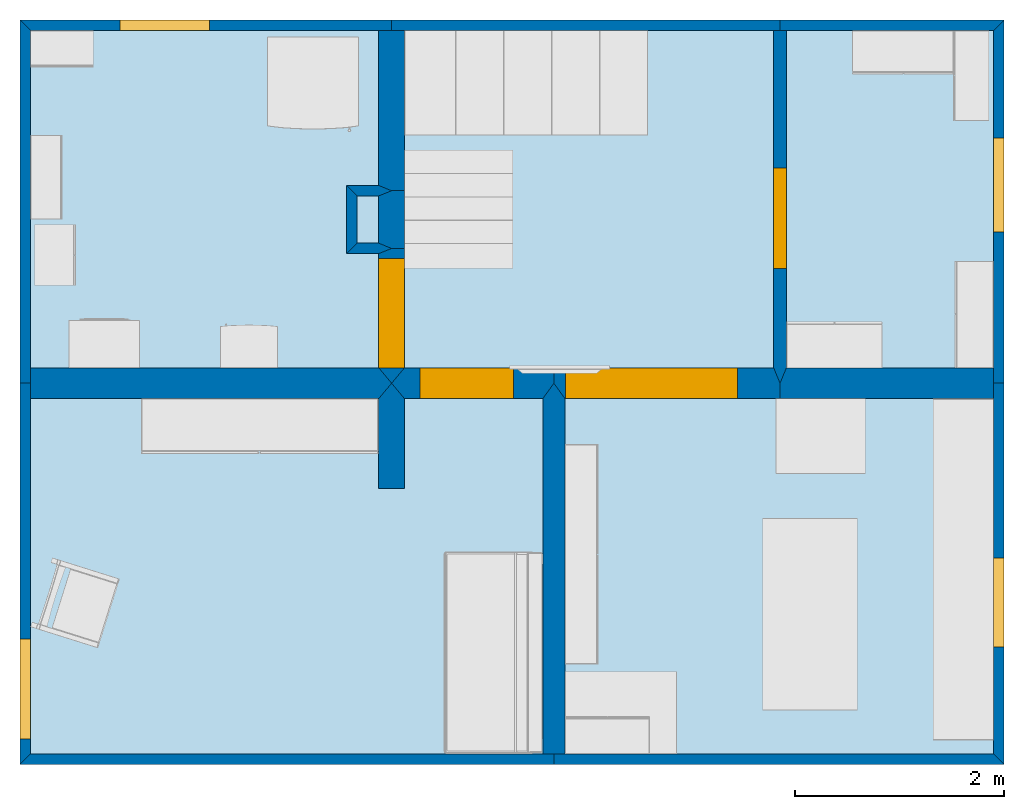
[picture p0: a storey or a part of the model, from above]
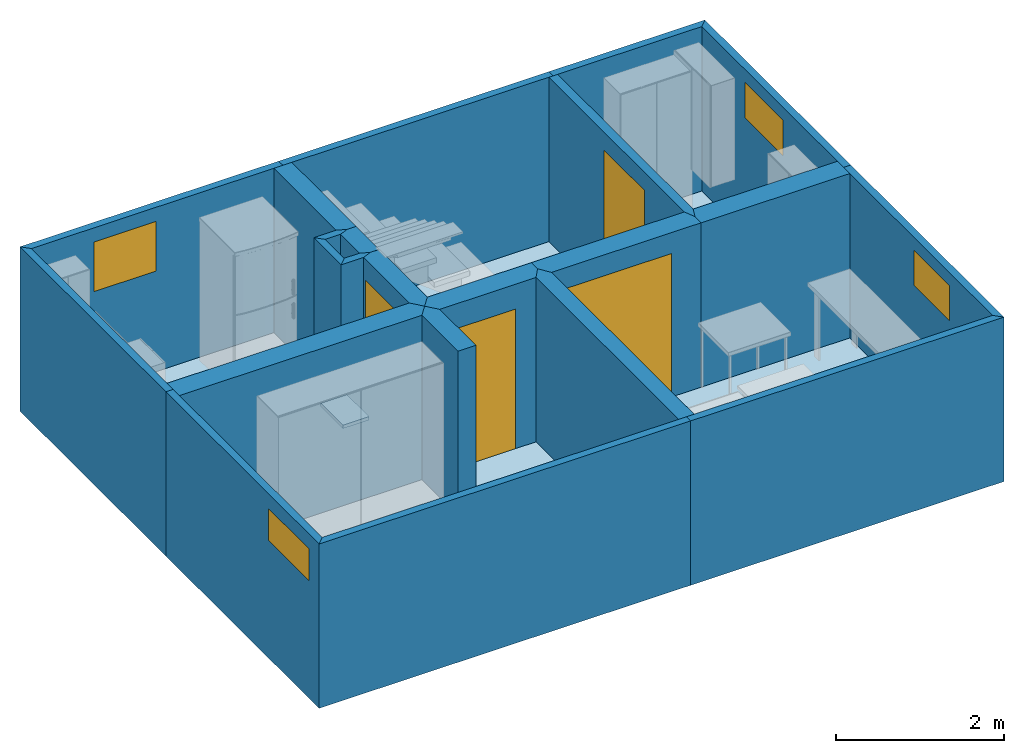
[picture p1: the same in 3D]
Properties of the parts of a building model (IFC4)

# File
Description: ViewDefinition [CoordinationView]
Time: 2025-05-14T06:58:39
Author: Metaroom
Written by: IfcOpenShell v0.7.0-f7c03db75
Made in: INDUSTRY_FOUNDATION_CLASSES_4

# IfcSite, Site
MetaroomProperties - NorthHeading: (np.float64(-0.077), np.float64(0.997), np.float64(0.0)); UpVector: (np.float64(0.0), np.float64(0.0), np.float64(1.0)); IsLeftHandedCoordinateSystem: no

# IfcBuilding, Building
Pset_BuildingCommon - NumberOfStoreys: 3

# IfcBuildingStorey (3)
In: Building
Pset_BuildingStoreyCommon - EntranceLevel: no; GrossPlannedArea: 0 m2; NetPlannedArea: 0 m2
Qto_BuildingStoreyBaseQuantities - GrossHeight: 0 m; NetHeight: 0 m; GrossPerimeter: 0 m; GrossFloorArea: 0 m2; NetFloorArea: 0 m2; GrossVolume: 0; NetVolume: 0
Name | Elevation (m)
Story 0 | 0.05
Story 1 | 2.86083
Story 2 | 5.71135

# IfcSpace (20)
Type - PredefinedType: SPACE
Name | In
001 | Story 0
002 | Story 0
003 | Story 0
004 | Story 0
005 | Story 0
006 | Story 0
007 | Story 1
008 | Story 1
009 | Story 1
010 | Story 1
011 | Story 1
012 | Story 2
013 | Story 2
014 | Story 2
015 | Story 2
016 | Story 2
017 | Story 2
018 | Story 2
019 | Story 2
020 | Story 2

# IfcBuildingElementProxy: PointOfInterest (6)
MetaroomProperties - Tag 0: Green
Name | In
PointOfInterest | 012
PointOfInterest | 014
PointOfInterest | 015
PointOfInterest | 016
PointOfInterest | 019
PointOfInterest | 019 | MetaroomProperties - Name: Test

# IfcDoor: Metaroom Door area (17)
Type - PredefinedType: DOOR
Name | In | OverallHeight (m) | OverallWidth (m)
Metaroom Door area | Story 2 | 2.28109 | 0.85378
Metaroom Door area | Story 2 | 2.25869 | 0.809477
Metaroom Door area | Story 2 | 2.47688 | 0.824479
Metaroom Door area | Story 2 | 2.28495 | 0.862626
Metaroom Door area | Story 2 | 2.47688 | 0.857412
Metaroom Door area | Story 1 | 2.05556 | 0.740228
Metaroom Door area | Story 1 | 2.10004 | 0.906087
Metaroom Door area | Story 1 | 2.1948 | 0.947792
Metaroom Door area | Story 1 | 2.2057 | 0.79263
Metaroom Door area | Story 1 | 2.12237 | 0.876066
Metaroom Door area | Story 1 | 2.24737 | 2.58648
Metaroom Door area | Story 1 | 2.08665 | 0.840058
Metaroom Door area | Story 1 | 2.11225 | 0.921124
Metaroom Door area | Story 0 | 2.12788 | 0.961672
Metaroom Door area | Story 0 | 2.08591 | 1.64665
Metaroom Door area | Story 0 | 2.08575 | 1.16787
Metaroom Door area | Story 0 | 2.02951 | 0.895735

# IfcEnergyConversionDevice, s5
In: 016
Type - Material: Wood light 0.01 m
MetaroomProperties - Name: s5

# IfcFlowTerminal (3)
Type - Material: Wood light 0.01 m
Name | In | Name
sb1 | 015 | sb1
s1 | 016 | s1
s7 | 016 | s7

# IfcFurniture (11)
PredefinedType: USERDEFINED
Name | In | Name
test1 | 015 | test1
test2 | 015 | test2
tes t 3 | 015 | tes t 3
s2 | 016 | s2
sb2 | 016 | sb2
s4 | 016 | s4
s6 | 016 | s6
s3 | 016 | s3
box | 016 | box
test 5 | 019 | test 5
test 6 | 019 | test 6

# IfcFurniture: Bathtub
In: 013
Type - ElementType: Bathtub; PredefinedType: USERDEFINED

# IfcFurniture: Bed (4)
Type - ElementType: Bed; PredefinedType: USERDEFINED
Name | In
Bed | 012
Bed | 014
2 x Bed | 016

# IfcFurniture: Chair (17)
Type - ElementType: Chair; PredefinedType: USERDEFINED
Name | In
Chair | 012
Chair | 014
2 x Chair | 015
Chair | 016
Chair | 008
10 x Chair | 009
Chair | 003

# IfcFurniture: Oven
In: 009
Type - ElementType: Oven; PredefinedType: USERDEFINED

# IfcFurniture: Refrigerator (3)
Type - ElementType: Refrigerator; PredefinedType: USERDEFINED
Name | In
Refrigerator | 009
2 x Refrigerator | 005

# IfcFurniture: STAIRS (5)
Type - ElementType: STAIRS; PredefinedType: USERDEFINED
Name | In
STAIRS | 019
2 x STAIRS | 011
2 x STAIRS | 002

# IfcFurniture: Sink (3)
Type - ElementType: Sink; PredefinedType: USERDEFINED
Name | In
Sink | 013
Sink | 009
Sink | 010

# IfcFurniture: Sofa (3)
Type - ElementType: Sofa; PredefinedType: USERDEFINED
Name | In
2 x Sofa | 009
Sofa | 003

# IfcFurniture: Storage (35)
Type - ElementType: Storage; PredefinedType: USERDEFINED
Name | In
2 x Storage | 012
2 x Storage | 013
2 x Storage | 014
Storage | 015
2 x Storage | 016
11 x Storage | 009
Storage | 010
3 x Storage | 011
5 x Storage | 001
Storage | 003
2 x Storage | 004
3 x Storage | 005

# IfcFurniture: Table (11)
Type - ElementType: Table; PredefinedType: USERDEFINED
Name | In
Table | 012
Table | 014
Table | 015
Table | 016
Table | 008
Table | 009
Table | 010
4 x Table | 004

# IfcFurniture: Television (2)
Type - ElementType: Television; PredefinedType: USERDEFINED
Name | In
Television | 009
Television | 002

# IfcFurniture: Toilet (2)
Type - ElementType: Toilet; PredefinedType: USERDEFINED
Name | In
Toilet | 013
Toilet | 010

# IfcFurniture: Washerdryer
In: 005
Type - ElementType: Washerdryer; PredefinedType: USERDEFINED

# IfcOpeningElement: OPENING (33)
Qto_OpeningElementBaseQuantities - Volume: 0
Name | In | Width (m) | Height (m) | Perimeter (m) | Area (m2)
Metaroom Opening | Story 2 | 0.889001 | 1.20373 | 4.18546 | 1.07012
Metaroom Opening | Story 2 | 0.85378 | 2.28109 | 6.26974 | 1.94755
Metaroom Opening | Story 2 | 0.89696 | 1.30003 | 4.39398 | 1.16608
Metaroom Opening | Story 2 | 0.835934 | 1.17514 | 4.02214 | 0.982337
Metaroom Opening | Story 2 | 2.25869 | 0.809477 | 6.13633 | 1.82836
Metaroom Opening | Story 2 | 0.82448 | 2.47688 | 6.60272 | 2.04214
Metaroom Opening | Story 2 | 1.74621 | 1.28411 | 6.06064 | 2.24233
Metaroom Opening | Story 2 | 2.28495 | 0.862626 | 6.29516 | 1.97106
Metaroom Opening | Story 2 | 1.81029 | 1.26005 | 6.14068 | 2.28106
Metaroom Opening | Story 2 | 0.926479 | 1.20518 | 4.26333 | 1.11658
Metaroom Opening | Story 2 | 0.912154 | 1.19392 | 4.21215 | 1.08904
Metaroom Opening | Story 2 | 0.857411 | 2.47688 | 6.66859 | 2.12371
Metaroom Opening | Story 2 | 0.847895 | 1.14438 | 3.98455 | 0.970312
Metaroom Opening | Story 1 | 0.458122 | 1.03326 | 2.98277 | 0.47336
Metaroom Opening | Story 1 | 2.05556 | 0.740228 | 5.59157 | 1.52158
Metaroom Opening | Story 1 | 2.10004 | 0.906087 | 6.01226 | 1.90282
Metaroom Opening | Story 1 | 0.844887 | 1.10469 | 3.89916 | 0.933341
Metaroom Opening | Story 1 | 2.1948 | 0.947791 | 6.28518 | 2.08021
Metaroom Opening | Story 1 | 0.951705 | 1.22256 | 4.34853 | 1.16352
Metaroom Opening | Story 1 | 2.2057 | 0.79263 | 5.99666 | 1.7483
Metaroom Opening | Story 1 | 2.12237 | 0.876066 | 5.99687 | 1.85934
Metaroom Opening | Story 1 | 2.24737 | 2.58648 | 9.66769 | 5.81276
Metaroom Opening | Story 1 | 0.529042 | 0.975744 | 3.00957 | 0.51621
Metaroom Opening | Story 1 | 2.08666 | 0.840058 | 5.85343 | 1.75291
Metaroom Opening | Story 1 | 2.11226 | 0.921124 | 6.06676 | 1.94565
Metaroom Opening | Story 0 | 0.899296 | 0.516043 | 2.83068 | 0.464075
Metaroom Opening | Story 0 | 2.12788 | 0.961672 | 6.1791 | 2.04632
Metaroom Opening | Story 0 | 1.64665 | 2.08591 | 7.46511 | 3.43475
Metaroom Opening | Story 0 | 1.16787 | 2.08575 | 6.50724 | 2.43589
Metaroom Opening | Story 0 | 0.895735 | 2.02951 | 5.8505 | 1.81791
Metaroom Opening | Story 0 | 0.960611 | 0.461575 | 2.84437 | 0.443394
Metaroom Opening | Story 0 | 0.850732 | 0.509087 | 2.71964 | 0.433096
Metaroom Opening | Story 0 | 0.857327 | 0.721237 | 3.15713 | 0.618336

# IfcSlab: Metaroom Ceiling (9)
In: Story 2
Type - PredefinedType: ROOF

# IfcSlab: Metaroom Slab (20)
Type - PredefinedType: FLOOR
Name | In
9 x Floor | Story 2
5 x Floor | Story 1
6 x Floor | Story 0

# IfcWallStandardCase: Metaroom Wall (82)
Type - PredefinedType: STANDARD
Pset_WallCommon - IsExternal: no; ExtendToStructure: yes
Qto_WallBaseQuantities - Width: 0 m; GrossSideArea: 0 m2; NetSideArea: 0 m2; GrossVolume: 0; NetVolume: 0; GrossWeight: 0; NetWeight: 0
Name | In | Length (m) | Height (m) | GrossFootprintArea (m2) | NetFootprintArea (m2)
Wall | Story 2 | 1.75784 | 2.50099 | 4.39634 | 4.39634
Wall | Story 2 | 3.59487 | 2.50099 | 8.99071 | 7.9206
Wall | Story 2 | 1.26897 | 2.50099 | 3.17369 | 1.22614
Wall | Story 2 | 2.50099 | 2.74129 | 6.85592 | 5.68985
Wall | Story 2 | 2.76837 | 2.50099 | 6.92365 | 6.92365
Wall | Story 2 | 1.25651 | 2.50099 | 3.14252 | 3.14252
Wall | Story 2 | 0.82073 | 2.50099 | 2.05264 | 2.05264
Wall | Story 2 | 1.24521 | 2.50099 | 3.11425 | 3.11425
Wall | Story 2 | 0.899919 | 2.50099 | 2.25069 | 2.25069
Wall | Story 2 | 3.12967 | 2.50099 | 7.82726 | 7.82726
Wall | Story 2 | 0.824903 | 2.50099 | 2.06307 | 2.06307
Wall | Story 2 | 2.28899 | 2.50099 | 5.72475 | 5.72475
Wall | Story 2 | 1.98471 | 2.50099 | 4.96374 | 3.9814
Wall | Story 2 | 1.20083 | 2.50099 | 3.00326 | 1.1749
Wall | Story 2 | 0.204017 | 2.50099 | 0.510243 | 0.510243
Wall | Story 2 | 0.297027 | 2.50099 | 0.742861 | 0.742861
Wall | Story 2 | 0.176833 | 2.50099 | 0.442256 | 0.442256
Wall | Story 2 | 0.896518 | 2.50099 | 2.24218 | 2.24218
Wall | Story 2 | 0.552419 | 2.50099 | 1.38159 | 1.38159
Wall | Story 2 | 1.03663 | 2.50099 | 2.5926 | 0.550464
Wall | Story 2 | 2.50099 | 1.51912 | 3.7993 | 3.7993
Wall | Story 2 | 2.50099 | 3.44103 | 8.60597 | 6.36364
2 x Wall | Story 2 | 0.465101 | 2.50099 | 1.16321 | 1.16321
Wall | Story 2 | 0.683547 | 2.50099 | 1.70954 | 1.70954
Wall | Story 2 | 3.51766 | 2.50099 | 8.79761 | 8.79761
Wall | Story 2 | 3.60023 | 2.50099 | 9.00414 | 9.00414
Wall | Story 2 | 2.50099 | 1.32459 | 3.31279 | 1.34173
Wall | Story 2 | 3.25928 | 2.50099 | 8.15142 | 5.87036
Wall | Story 2 | 1.61245 | 2.50099 | 4.03272 | 4.03272
Wall | Story 2 | 2.50099 | 0.824902 | 2.06307 | 2.06307
Wall | Story 2 | 2.50099 | 0.204018 | 0.510246 | 0.510246
Wall | Story 2 | 3.60023 | 2.50099 | 9.00414 | 7.88756
Wall | Story 2 | 3.07252 | 2.50099 | 7.68432 | 6.59528
Wall | Story 2 | 2.50099 | 1.0037 | 2.51024 | 2.51024
Wall | Story 2 | 2.50099 | 1.0399 | 2.60077 | 0.47706
Wall | Story 2 | 2.50099 | 0.325363 | 0.813729 | 0.813729
Wall | Story 2 | 2.50099 | 0.552419 | 1.38159 | 1.38159
Wall | Story 2 | 2.50099 | 2.48224 | 6.20806 | 5.23775
Wall | Story 1 | 2.52996 | 0.562362 | 1.42275 | 1.42275
2 x Wall | Story 1 | 0.36311 | 2.52996 | 0.918652 | 0.918652
Wall | Story 1 | 0.562362 | 2.52996 | 1.42275 | 1.42275
Wall | Story 1 | 1.739 | 2.52996 | 4.39959 | 3.92622
2 x Wall | Story 1 | 1.87732 | 2.52996 | 4.74953 | 4.74953
Wall | Story 1 | 2.52996 | 1.87732 | 4.74953 | 4.74953
Wall | Story 1 | 2.52996 | 1.739 | 4.39958 | 2.878
Wall | Story 1 | 0.194856 | 2.52996 | 0.492978 | 0.492978
Wall | Story 1 | 3.86355 | 2.52996 | 9.77461 | 7.87178
Wall | Story 1 | 2.52996 | 0.202023 | 0.511109 | 0.511109
Wall | Story 1 | 2.52996 | 1.52503 | 3.85825 | 3.85825
Wall | Story 1 | 3.54303 | 2.52996 | 8.96372 | 8.03038
Wall | Story 1 | 7.06928 | 2.52996 | 17.885 | 14.6412
Wall | Story 1 | 9.3397 | 2.52996 | 23.629 | 14.2086
Wall | Story 1 | 1.41894 | 2.52996 | 3.58985 | 3.58985
Wall | Story 1 | 3.39973 | 2.52996 | 8.60116 | 8.60116
Wall | Story 1 | 1.76733 | 2.52996 | 4.47127 | 3.95506
Wall | Story 1 | 1.76733 | 2.52996 | 4.47127 | 2.71836
Wall | Story 1 | 2.52996 | 3.86355 | 9.77461 | 7.82896
Wall | Story 0 | 3.37781 | 2.39036 | 8.07419 | 7.61011
Wall | Story 0 | 3.37781 | 2.39036 | 8.07419 | 6.02787
Wall | Story 0 | 2.39036 | 2.04437 | 4.88678 | 4.88678
Wall | Story 0 | 2.39036 | 2.04437 | 4.88679 | 4.88679
Wall | Story 0 | 2.39036 | 2.16524 | 5.17572 | 1.74097
Wall | Story 0 | 2.39036 | 3.719 | 8.88976 | 8.88976
Wall | Story 0 | 2.39036 | 1.29079 | 3.08546 | 0.649576
Wall | Story 0 | 2.39036 | 1.55375 | 3.71404 | 1.89613
Wall | Story 0 | 2.39036 | 0.552409 | 1.32046 | 1.32046
Wall | Story 0 | 2.39036 | 1.53461 | 3.66826 | 3.66826
Wall | Story 0 | 3.54881 | 2.39036 | 8.48294 | 8.48294
Wall | Story 0 | 3.54881 | 2.39036 | 8.48294 | 8.03955
Wall | Story 0 | 5.01147 | 2.39036 | 11.9792 | 11.9792
Wall | Story 0 | 3.45771 | 2.39036 | 8.26519 | 8.26519
Wall | Story 0 | 1.00886 | 2.39036 | 2.41154 | 2.41154
Wall | Story 0 | 3.54881 | 2.39036 | 8.48294 | 8.04984
Wall | Story 0 | 4.20961 | 2.39036 | 10.0625 | 10.0625
2 x Wall | Story 0 | 0.381453 | 2.39036 | 0.911812 | 0.911812
Wall | Story 0 | 0.552409 | 2.39036 | 1.32046 | 1.32046
Wall | Story 0 | 3.45771 | 2.39036 | 8.26519 | 7.64686
Wall | Story 0 | 2.39036 | 3.37781 | 8.07419 | 8.07419

# IfcWindow: Metaroom Window area (16)
Type - PredefinedType: WINDOW
OverallHeight: 1.5 m; OverallWidth: 0.5 m
Name | In
8 x Metaroom Window area | Story 2
4 x Metaroom Window area | Story 1
4 x Metaroom Window area | Story 0
